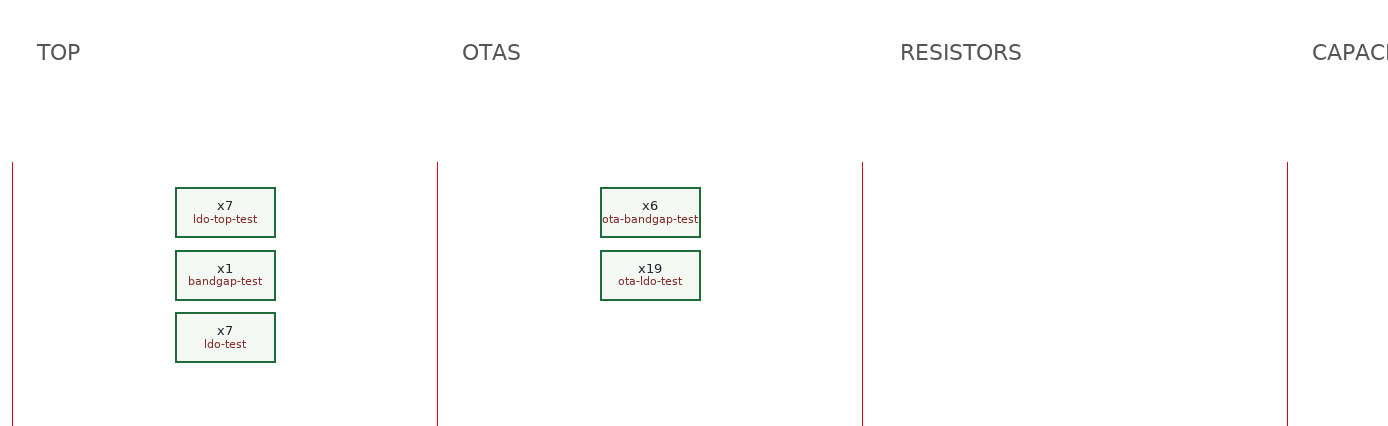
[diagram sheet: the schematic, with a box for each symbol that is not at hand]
v {xschem version=3.4.4 file_version=1.2
}
G {}
K {}
V {}
S {}
E {}
L 7 20 -300 20 -60 {}
L 7 360 -300 360 -60 {}
L 7 700 -300 700 -60 {}
L 7 1040 -300 1040 -60 {}
L 7 1380 -300 1380 -60 {}
T {TOP} 40 -400 0 0 0.8 0.8 {}
T {OTAS} 380 -400 0 0 0.8 0.8 {}
T {RESISTORS} 730 -400 0 0 0.8 0.8 {}
T {CAPACITORS} 1060 -400 0 0 0.8 0.8 {}
C {devices/title.sym} 160 -30 0 0 {name=l5 author="LDO by CHIP-USM"}
C {ldo-top-test.sym} 190 -260 0 0 {name=x7}
C {ota-bandgap-test.sym} 530 -260 0 0 {name=x6}
C {ota-ldo-test.sym} 530 -210 0 0 {name=x19}
C {bandgap-test.sym} 190 -210 0 0 {name=x1}
C {ldo-test.sym} 190 -160 0 0 {name=x7}
